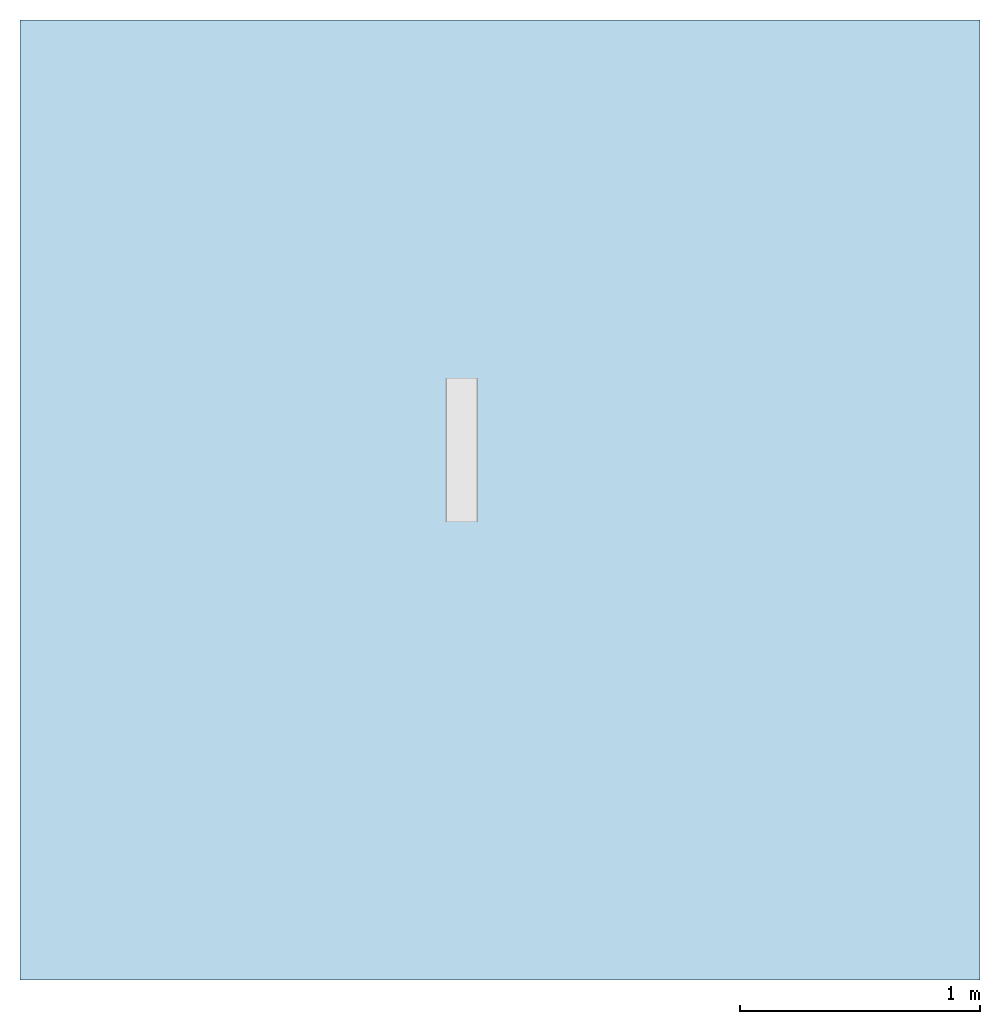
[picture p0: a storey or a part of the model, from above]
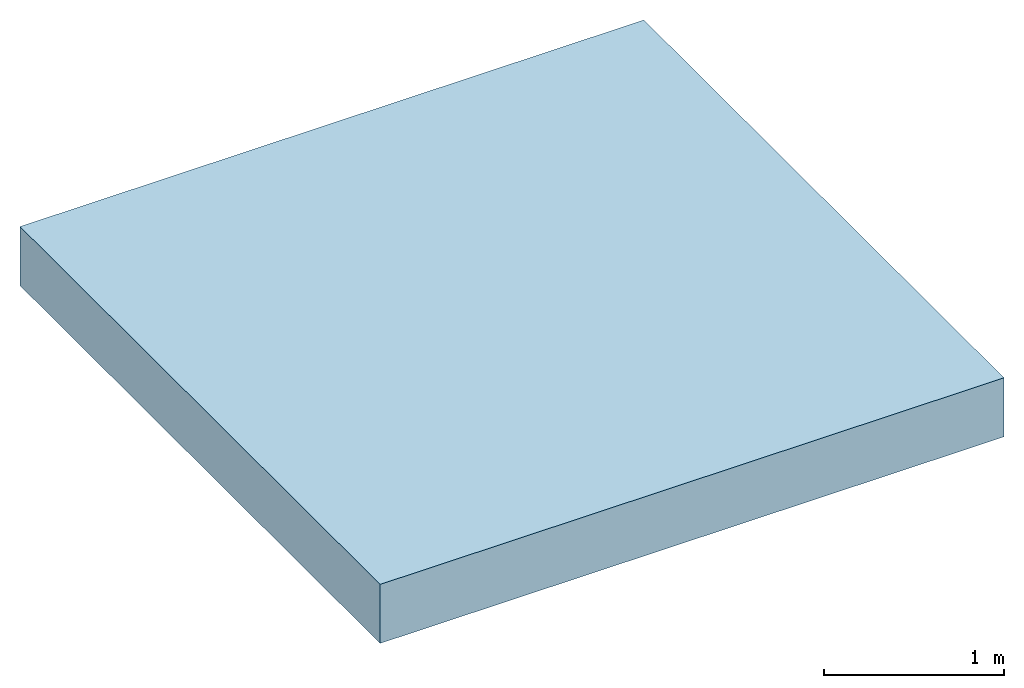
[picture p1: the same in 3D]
Properties of the parts of a building model (IFC2X3)

# File
Description: ViewDefinition [CoordinationView]
File name: Project Number
Time: 2014-06-06T11:20:41
Written by: The EXPRESS Data Manager Version 5.01.0100.02.64mod : 6 Jun 2012
Made in: 20130308_1515(x64) - Exporter 2014.0.2013.0308 - Default UI
Comment: STEP Physical File produced by: The EXPRESS Data Manager Version 5.01.0100.02.64mod : 6 Jun 2012 * Module: EDMstepFileFactory/EDMstandAlone * Creation date: Fri Jun 06 11:20:41 2014 * Host: IN-BLR-PC-0010 * Database: C:\Users\palleri\AppData\Local\Temp\{503E0F08-E6A4-48D4-93E2-07DFC66215DA}\ifc * Database version: 5507 * Database creation date: Fri Jun 06 11:20:40 2014 * Schema: IFC2X3 * Model: DataRepository.ifc * Model creation date: Fri Jun 06 11:20:40 2014 * Header model: DataRepository.ifc_HeaderModel * Header model creation date: Fri Jun 06 11:20:40 2014 * EDMuser: sdai-user * EDMgroup: sdai-group * License ID and type: 5605 : Permanent license. Expiry date: * EDMstepFileFactory options: 020000

# IfcProject, Project Number
LongName: Project Name; Phase: Project Status

# IfcSite, Default
RefLatitude: 42, 21, 30, 344238; RefLongitude: -71, -3, -35, -194702; RefElevation: 0 mm

# IfcBuilding
Pset_BuildingCommon - NumberOfStoreys: 1
Other - Project Issue Date: Issue Date; Project Number: Project Number; Project Address: ## Street City, State Zip; Project Status: Project Status; Project Name: Project Name; Client Name: Owner

# IfcBuildingStorey, Level 1
LongName: Level 1; Elevation: 0 mm
Constraints - Elevation Base: Project Base Point; Elevation: 0 mm
Graphics - Symbol at End 2 Default: yes; Symbol: M_Level Head - Circle: M_Level Head - Circle; Line Pattern: Center; Symbol at End 1 Default: no; Color: 0; Line Weight: 1
Identity Data - Name: Level 1; Structural: no; Building Story: yes
Dimensions - Computation Height: 0 mm

# IfcFlowTerminal: 36838 - Adjustable Length Channel - Intermediate Section - 600mm LG, ACO Freedeck Adjustable Length (Accessories part 2) V1.12 - Stainless Steel:36838 - Adjustable Length Channel - Intermediate Section - 600mm LG:280767
In: Level 1
Material: Stainless Steel Grade 304
Model Properties - Grating Product Code 36954: Load Class A15 - Mesh Grating - 14mm x 30mm Mesh - Stainless Steel 304 - 500mm long - 1.6kg; Grating Product Code 00273: Load Class A15 - Slotted Grating - 10 x 80mm Slot - Stainless Steel 304 - 500mm long - 1.0kg
Materials and Finishes - Material: Stainless Steel Grade 304
Dimensions - Adjustable Corner Angle: 91 deg; Height @ Invert 1: 165 mm; Grating End Length: 600 mm; Channel Length: 600 mm; Channel End Length: -600 mm; Height @ Invert 2: 165 mm; Corner Angle Gravel Guard: 73 mm; Corner Angle Void Position: 5000 mm
Other - Height @ Invert 1 Min & Max: 105 mm; Corner Angle Invert Height Min & Max: 75 mm; Corner Angle Value: 91 deg; Top Piece Void Height @ Invert 2: 45 mm; Height @ Invert 2 Min & Max: 105 mm; Nos: 20; Top Piece Void Height @ Invert 1: 45 mm; Top Void Position: 0 mm; Top Height: 65 mm; Adjustable Length Shallow Section: no; Corner Angle Fixed Height: no; Adjustable Length Channel: yes; Adjustable Length Intermediate Section: yes; Base Height: 60 mm; Corner Angle Adjustable Height: no; Adjustable Length Deep Section: no
Phasing - Phase Created: New Construction
Constraints - Moves With Nearby Elements: no; Level: Level: Level 1
Identity Data - Mark: 16; Manufacturer: ACO Building Drainage; Watermark1: This file is the property of ACO Technologies PLC; Watermark2: This file is water marked and users are prohibited to reproduce, adapt, distribute this information; E-mail Technical: abdtechnical@aco.co.uk; Watermarked By: www.acobd.com; E-mail Sales: abdcommercial@aco.co.uk; Website: www.acobd.com; Watermarked With: BIM Manager Premium Suite; Telephone: +44 (0)1462 816666; Address: ACO Business Centre, Caxton Road, Bedford, MK41 0LF; Fax: +44 (0)1462 851490
Construction - Corner Angle Shallow Section: no; Corner Angle Intermediate Section: no; 36954 - Grating - Plain Mesh - Stainless Steel 304 - 500mm long: yes; 00273 - Grating - Slotted Grating - Stainless Steel 304 - 500mm long: no
Pset_ManufacturerTypeInformation - Manufacturer: ACO Building Drainage
General - Product Standard: BS EN 1433:2002, CE marked; Load Class: A15; Channel Colour: Mid Grey; Channel Recyclable: Fully recyclable; NBS Specification: NBS Section R10 Gravity Rainwater Drainage Systems, Subsection 365; Weight (Kg): 2.2kg; Channel Recycled Material Content: 60 - 70 %; Product Code: 36838; Maintenance Guidelines: X:\Electronic Literature\ABD Electronic Literature\Roof and Balcony Drainage\ACO Freedeck Brochure.pdf; Dimensions (LxWxH): 140 x 600; Price: POA - contact ACO; Product Range: ACO Freedeck; Channel Material: Stainless Steel Grade 304; Installation Guidelines: X:\Electronic Literature\ABD Electronic Literature\Roof and Balcony Drainage\ACO Freedeck Brochure.pdf; Product Type: Linear Deck Drainage System; Product Description: ACO Freedeck Adjustable Channel - Intermediate Section

# IfcOpeningElement: Opening (120)
In: Level 1
Model Properties - Grating Product Code 36954: Load Class A15 - Mesh Grating - 14mm x 30mm Mesh - Stainless Steel 304 - 500mm long - 1.6kg; Grating Product Code 00273: Load Class A15 - Slotted Grating - 10 x 80mm Slot - Stainless Steel 304 - 500mm long - 1.0kg
Materials and Finishes - Material: Stainless Steel Grade 304
Dimensions - Adjustable Corner Angle: 91 deg; Height @ Invert 1: 165 mm; Grating End Length: 600 mm; Channel Length: 600 mm; Channel End Length: -600 mm; Height @ Invert 2: 165 mm; Corner Angle Gravel Guard: 73 mm; Corner Angle Void Position: 5000 mm
Other - Height @ Invert 1 Min & Max: 105 mm; Corner Angle Invert Height Min & Max: 75 mm; Corner Angle Value: 91 deg; Top Piece Void Height @ Invert 2: 45 mm; Height @ Invert 2 Min & Max: 105 mm; Nos: 20; Top Piece Void Height @ Invert 1: 45 mm; Top Void Position: 0 mm; Top Height: 65 mm; Adjustable Length Shallow Section: no; Corner Angle Fixed Height: no; Adjustable Length Channel: yes; Adjustable Length Intermediate Section: yes; Base Height: 60 mm; Corner Angle Adjustable Height: no; Adjustable Length Deep Section: no
Phasing - Phase Created: New Construction
Constraints - Moves With Nearby Elements: no; Level: Level: Level 1
Identity Data - Mark: 16; Manufacturer: ACO Building Drainage; Watermark1: This file is the property of ACO Technologies PLC; Watermark2: This file is water marked and users are prohibited to reproduce, adapt, distribute this information; E-mail Technical: abdtechnical@aco.co.uk; Watermarked By: www.acobd.com; E-mail Sales: abdcommercial@aco.co.uk; Website: www.acobd.com; Watermarked With: BIM Manager Premium Suite; Telephone: +44 (0)1462 816666; Address: ACO Business Centre, Caxton Road, Bedford, MK41 0LF; Fax: +44 (0)1462 851490
Construction - Corner Angle Shallow Section: no; Corner Angle Intermediate Section: no; 36954 - Grating - Plain Mesh - Stainless Steel 304 - 500mm long: yes; 00273 - Grating - Slotted Grating - Stainless Steel 304 - 500mm long: no
Pset_ManufacturerTypeInformation - Manufacturer: ACO Building Drainage
General - Product Standard: BS EN 1433:2002, CE marked; Load Class: A15; Channel Colour: Mid Grey; Channel Recyclable: Fully recyclable; NBS Specification: NBS Section R10 Gravity Rainwater Drainage Systems, Subsection 365; Weight (Kg): 2.2kg; Channel Recycled Material Content: 60 - 70 %; Product Code: 36838; Maintenance Guidelines: X:\Electronic Literature\ABD Electronic Literature\Roof and Balcony Drainage\ACO Freedeck Brochure.pdf; Dimensions (LxWxH): 140 x 600; Price: POA - contact ACO; Product Range: ACO Freedeck; Channel Material: Stainless Steel Grade 304; Installation Guidelines: X:\Electronic Literature\ABD Electronic Literature\Roof and Balcony Drainage\ACO Freedeck Brochure.pdf; Product Type: Linear Deck Drainage System; Product Description: ACO Freedeck Adjustable Channel - Intermediate Section
Name (ACO Freedeck Adjustable Length (Accessories part 2) V1.12 - Stainless Steel:36838 - Adjustable Length Channel - Intermediate Section - 600mm LG:280767:...)
1
2
3
4
5
6
7
8
9
10
11
12
13
14
15
16
17
18
19
20
21
22
23
24
25
26
27
28
29
30
31
32
33
34
35
36
37
38
39
40
41
42
43
44
45
46
47
48
49
50
51
52
53
54
55
56
57
58
59
60
61
62
63
64
65
66
67
68
69
70
71
72
73
74
75
76
77
78
79
80
81
82
83
84
85
86
87
88
89
90
91
92
93
94
95
96
97
98
99
100
101
102
103
104
105
106
107
108
109
110
111
112
113
114
115
116
117
118
119
120

# IfcOpeningElement: Recess (2)
In: Level 1
Constraints - Room Bounding: yes; Level: Level: Level 1; Height Offset From Level: 0 mm; Related to Mass: no
Dimensions - Volume: 6.39167 m3; Area: 16 m2; Thickness: 400 mm; Perimeter: 16000 mm
Phasing - Phase Created: New Construction
Structural - Enable Analytical Model: no; Structural: no
Graphics - Coarse Scale Fill Color: 0
Analytical Properties - Absorptance: 0.1; Roughness: 1; Thermal Resistance (R): 0.382409; Heat Transfer Coefficient (U): 2.615; Thermal mass: 604440
Construction - Function: Interior; Default Thickness: 400 mm
Materials and Finishes - Structural Material: Concrete, Broom Finish

# IfcSlab: Floor:Generic Floor - 400mm, Floor:Generic Floor - 400mm:193825
In: Level 1
PredefinedType: FLOOR; Material: Concrete, Broom Finish 400 mm
Constraints - Room Bounding: yes; Level: Level: Level 1; Height Offset From Level: 0 mm; Related to Mass: no
Dimensions - Volume: 6.39167 m3; Area: 16 m2; Thickness: 400 mm; Perimeter: 16000 mm
Phasing - Phase Created: New Construction
Structural - Enable Analytical Model: no; Structural: no
Pset_SlabCommon - Reference: Generic Floor - 400mm; IsExternal: no; LoadBearing: yes; ThermalTransmittance: 2.615 kg/K/s3
Graphics - Coarse Scale Fill Color: 0
Analytical Properties - Absorptance: 0.1; Roughness: 1; Thermal Resistance (R): 0.382409; Heat Transfer Coefficient (U): 2.615; Thermal mass: 604440
Construction - Function: Interior; Default Thickness: 400 mm
Materials and Finishes - Structural Material: Concrete, Broom Finish
